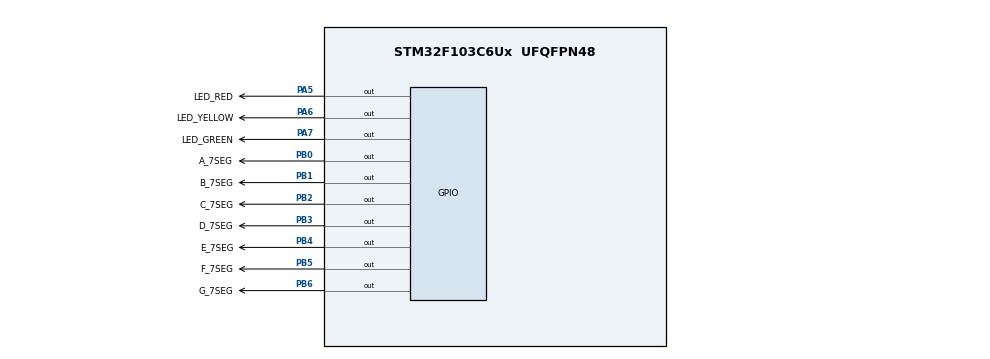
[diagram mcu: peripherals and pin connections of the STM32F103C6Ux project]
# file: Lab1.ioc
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Mcu.Family=STM32F1
Mcu.Name=STM32F103C6Ux
Mcu.Package=UFQFPN48
NVIC.PriorityGroup=NVIC_PRIORITYGROUP_4
PA5.GPIO_Label=LED_RED
PA5.Signal=GPIO_Output
PA6.GPIO_Label=LED_YELLOW
PA6.Signal=GPIO_Output
PA7.GPIO_Label=LED_GREEN
PA7.Signal=GPIO_Output
PB0.GPIO_Label=A_7SEG
PB0.Signal=GPIO_Output
PB1.GPIO_Label=B_7SEG
PB1.Signal=GPIO_Output
PB2.GPIO_Label=C_7SEG
PB2.Signal=GPIO_Output
PB3.GPIO_Label=D_7SEG
PB3.Signal=GPIO_Output
PB4.GPIO_Label=E_7SEG
PB4.Signal=GPIO_Output
PB5.GPIO_Label=F_7SEG
PB5.Signal=GPIO_Output
PB6.GPIO_Label=G_7SEG
PB6.Signal=GPIO_Output
ProjectManager.HeapSize=0x200
ProjectManager.StackSize=0x400
ProjectManager.TargetToolchain=STM32CubeIDE
RCC.APB1Freq_Value=8000000
RCC.APB2Freq_Value=8000000
VP_SYS_VS_ND.Mode=No_Debug
board=custom

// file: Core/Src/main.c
/* USER CODE BEGIN Header */
/**
  ******************************************************************************
  * @file           : main.c
  * @brief          : Main program body
  ******************************************************************************
  * @attention
  *
  * <h2><center>&copy; Copyright (c) 2024 STMicroelectronics.
  * All rights reserved.</center></h2>
  *
  * This software component is licensed by ST under BSD 3-Clause license,
  * the "License"; You may not use this file except in compliance with the
  * License. You may obtain a copy of the License at:
  *                        opensource.org/licenses/BSD-3-Clause
  *
  ******************************************************************************
  */
/* USER CODE END Header */
#include "main.h"

void SystemClock_Config(void);
static void MX_GPIO_Init(void);

/* USER CODE BEGIN 0 */
void clearAllClock(){
    // Array of pins for LEDs D1 to D12
    uint16_t ledPins[12] = {D1_Pin, D2_Pin, D3_Pin, D4_Pin,
                            D5_Pin, D6_Pin, D7_Pin, D8_Pin,
                            D9_Pin, D10_Pin, D11_Pin, D12_Pin};

    // Loop through each LED and turn it off
    for (int i = 0; i < 12; i++) {
        HAL_GPIO_WritePin(GPIOA, ledPins[i], RESET); // Turn off LED
    }
}
/* USER CODE END 0 */

int main(void)
{

  /* MCU Configuration--------------------------------------------------------*/

  /* Reset of all peripherals, Initializes the Flash interface and the Systick. */
  HAL_Init();

  /* Configure the system clock */
  SystemClock_Config();

  /* Initialize all configured peripherals */
  MX_GPIO_Init();

  /* Infinite loop */
  /* USER CODE BEGIN WHILE */
  uint16_t ledPins[12] = {D1_Pin, D2_Pin, D3_Pin, D4_Pin,
                            D5_Pin, D6_Pin, D7_Pin, D8_Pin,
                            D9_Pin, D10_Pin, D11_Pin, D12_Pin};

  while (1)
  {
    /* USER CODE END WHILE */

    /* USER CODE BEGIN 3 */
	  for (int i = 0; i < 12; i++)
	  {
		  HAL_GPIO_WritePin(GPIOA, ledPins[i], GPIO_PIN_SET); // Turn on LED
		  HAL_Delay(500); // Wait for 500 ms before lighting the next LED
	  }

	  HAL_Delay(1000);
	  clearAllClock(); // Turn off all LEDs simultaneously
	  HAL_Delay(2000);
  }
  /* USER CODE END 3 */
}

void SystemClock_Config(void)
{
  RCC_OscInitTypeDef RCC_OscInitStruct = {0};
  RCC_ClkInitTypeDef RCC_ClkInitStruct = {0};

  /** Initializes the RCC Oscillators according to the specified parameters
  * in the RCC_OscInitTypeDef structure.
  */
  RCC_OscInitStruct.OscillatorType = RCC_OSCILLATORTYPE_HSI;
  RCC_OscInitStruct.HSIState = RCC_HSI_ON;
  RCC_OscInitStruct.HSICalibrationValue = RCC_HSICALIBRATION_DEFAULT;
  RCC_OscInitStruct.PLL.PLLState = RCC_PLL_NONE;
  if (HAL_RCC_OscConfig(&RCC_OscInitStruct) != HAL_OK)
  {
    Error_Handler();
  }
  /** Initializes the CPU, AHB and APB buses clocks
  */
  RCC_ClkInitStruct.ClockType = RCC_CLOCKTYPE_HCLK|RCC_CLOCKTYPE_SYSCLK
                              |RCC_CLOCKTYPE_PCLK1|RCC_CLOCKTYPE_PCLK2;
  RCC_ClkInitStruct.SYSCLKSource = RCC_SYSCLKSOURCE_HSI;
  RCC_ClkInitStruct.AHBCLKDivider = RCC_SYSCLK_DIV1;
  RCC_ClkInitStruct.APB1CLKDivider = RCC_HCLK_DIV1;
  RCC_ClkInitStruct.APB2CLKDivider = RCC_HCLK_DIV1;

  if (HAL_RCC_ClockConfig(&RCC_ClkInitStruct, FLASH_LATENCY_0) != HAL_OK)
  {
    Error_Handler();
  }
}

static void MX_GPIO_Init(void)
{
  GPIO_InitTypeDef GPIO_InitStruct = {0};

  /* GPIO Ports Clock Enable */
  __HAL_RCC_GPIOA_CLK_ENABLE();

  /*Configure GPIO pin Output Level */
  HAL_GPIO_WritePin(GPIOA, D1_Pin|D2_Pin|D3_Pin|D4_Pin
                          |D5_Pin|D6_Pin|D7_Pin|D8_Pin
                          |D9_Pin|D10_Pin|D11_Pin|D12_Pin, GPIO_PIN_RESET);

  /*Configure GPIO pins : D1_Pin D2_Pin D3_Pin D4_Pin
                           D5_Pin D6_Pin D7_Pin D8_Pin
                           D9_Pin D10_Pin D11_Pin D12_Pin */
  GPIO_InitStruct.Pin = D1_Pin|D2_Pin|D3_Pin|D4_Pin
                          |D5_Pin|D6_Pin|D7_Pin|D8_Pin
                          |D9_Pin|D10_Pin|D11_Pin|D12_Pin;
  GPIO_InitStruct.Mode = GPIO_MODE_OUTPUT_PP;
  GPIO_InitStruct.Pull = GPIO_NOPULL;
  GPIO_InitStruct.Speed = GPIO_SPEED_FREQ_LOW;
  HAL_GPIO_Init(GPIOA, &GPIO_InitStruct);

}

void Error_Handler(void)
{
  __disable_irq();
  while (1)
  {
  }
}

/************************ (C) COPYRIGHT STMicroelectronics *****END OF FILE****/
